VERSION 5.8 ;
BUSBITCHARS "[]" ;
DIVIDERCHAR "/" ;
UNITS
    DATABASE MICRONS 1000 ;
END UNITS

VIA PLL_ANALOG_MACRO_via1_2_2200_440_1_5_410_410
  VIARULE via1Array ;
  CUTSIZE 0.19 0.19 ;
  LAYERS Metal1 Via1 Metal2 ;
  CUTSPACING 0.22 0.22 ;
  ENCLOSURE 0.05 0.125 0.005 0.05 ;
  ROWCOL 1 5 ;
END PLL_ANALOG_MACRO_via1_2_2200_440_1_5_410_410

VIA PLL_ANALOG_MACRO_via2_3_2200_440_1_5_410_410
  VIARULE via2Array ;
  CUTSIZE 0.19 0.19 ;
  LAYERS Metal2 Via2 Metal3 ;
  CUTSPACING 0.22 0.22 ;
  ENCLOSURE 0.005 0.05 0.05 0.005 ;
  ROWCOL 1 5 ;
END PLL_ANALOG_MACRO_via2_3_2200_440_1_5_410_410

VIA PLL_ANALOG_MACRO_via3_4_2200_440_1_5_410_410
  VIARULE via3Array ;
  CUTSIZE 0.19 0.19 ;
  LAYERS Metal3 Via3 Metal4 ;
  CUTSPACING 0.22 0.22 ;
  ENCLOSURE 0.05 0.005 0.005 0.05 ;
  ROWCOL 1 5 ;
END PLL_ANALOG_MACRO_via3_4_2200_440_1_5_410_410

VIA PLL_ANALOG_MACRO_via4_5_2200_440_1_5_410_410
  VIARULE via4Array ;
  CUTSIZE 0.19 0.19 ;
  LAYERS Metal4 Via4 Metal5 ;
  CUTSPACING 0.22 0.22 ;
  ENCLOSURE 0.005 0.05 0.05 0.005 ;
  ROWCOL 1 5 ;
END PLL_ANALOG_MACRO_via4_5_2200_440_1_5_410_410

VIA PLL_ANALOG_MACRO_via5_6_2200_440_1_2_840_840
  VIARULE viaTop1Array ;
  CUTSIZE 0.42 0.42 ;
  LAYERS Metal5 TopVia1 TopMetal1 ;
  CUTSPACING 0.42 0.42 ;
  ENCLOSURE 0.1 0.1 0.47 0.42 ;
  ROWCOL 1 2 ;
END PLL_ANALOG_MACRO_via5_6_2200_440_1_2_840_840

VIA PLL_ANALOG_MACRO_via6_7_5000_5000_2_2_1960_1960
  VIARULE viaTop2Array ;
  CUTSIZE 0.9 0.9 ;
  LAYERS TopMetal1 TopVia2 TopMetal2 ;
  CUTSPACING 1.06 1.06 ;
  ENCLOSURE 1.07 0.5 0.5 1.07 ;
  ROWCOL 2 2 ;
END PLL_ANALOG_MACRO_via6_7_5000_5000_2_2_1960_1960

VIA PLL_ANALOG_MACRO_via6_7_5000_2200_1_2_1960_1960
  VIARULE viaTop2Array ;
  CUTSIZE 0.9 0.9 ;
  LAYERS TopMetal1 TopVia2 TopMetal2 ;
  CUTSPACING 1.06 1.06 ;
  ENCLOSURE 1.07 0.5 0.5 0.65 ;
  ROWCOL 1 2 ;
END PLL_ANALOG_MACRO_via6_7_5000_2200_1_2_1960_1960

VIA PLL_ANALOG_MACRO_via6_7_2200_5000_2_1_1960_1960
  VIARULE viaTop2Array ;
  CUTSIZE 0.9 0.9 ;
  LAYERS TopMetal1 TopVia2 TopMetal2 ;
  CUTSPACING 1.06 1.06 ;
  ENCLOSURE 0.65 0.5 0.5 1.07 ;
  ROWCOL 2 1 ;
END PLL_ANALOG_MACRO_via6_7_2200_5000_2_1_1960_1960

VIA PLL_ANALOG_MACRO_via6_7_2200_2200_1_1_1960_1960
  VIARULE viaTop2Array ;
  CUTSIZE 0.9 0.9 ;
  LAYERS TopMetal1 TopVia2 TopMetal2 ;
  CUTSPACING 1.06 1.06 ;
  ENCLOSURE 0.65 0.5 0.5 0.65 ;
END PLL_ANALOG_MACRO_via6_7_2200_2200_1_1_1960_1960

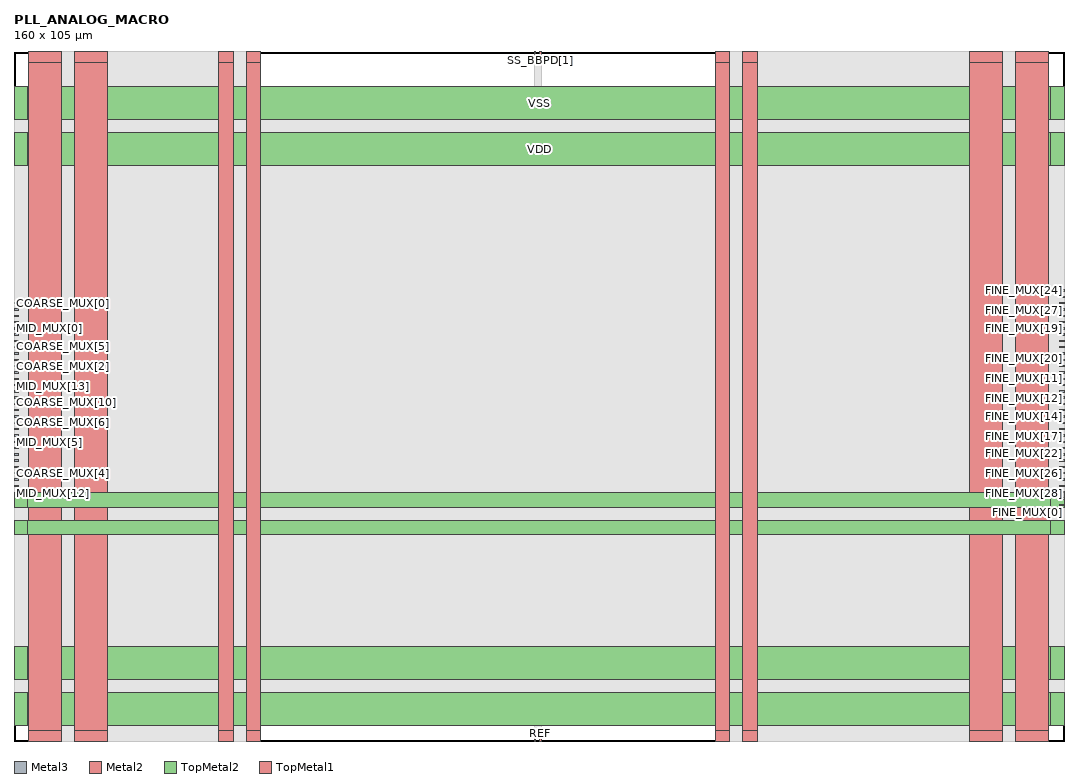
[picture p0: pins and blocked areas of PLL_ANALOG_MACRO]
MACRO PLL_ANALOG_MACRO
  FOREIGN PLL_ANALOG_MACRO 0 0 ;
  CLASS BLOCK ;
  SIZE 160 BY 105 ;
  PIN COARSE_MUX[0]
    DIRECTION INPUT ;
    USE SIGNAL ;
    PORT
      LAYER Metal3 ;
        RECT  0 66.62 0.72 66.82 ;
    END
  END COARSE_MUX[0]
  PIN COARSE_MUX[10]
    DIRECTION INPUT ;
    USE SIGNAL ;
    PORT
      LAYER Metal3 ;
        RECT  0 50.3 0.72 50.5 ;
    END
  END COARSE_MUX[10]
  PIN COARSE_MUX[11]
    DIRECTION INPUT ;
    USE SIGNAL ;
    PORT
      LAYER Metal3 ;
        RECT  0 53.18 0.72 53.38 ;
    END
  END COARSE_MUX[11]
  PIN COARSE_MUX[12]
    DIRECTION INPUT ;
    USE SIGNAL ;
    PORT
      LAYER Metal3 ;
        RECT  0 54.14 0.72 54.34 ;
    END
  END COARSE_MUX[12]
  PIN COARSE_MUX[13]
    DIRECTION INPUT ;
    USE SIGNAL ;
    PORT
      LAYER Metal3 ;
        RECT  0 44.54 0.72 44.74 ;
    END
  END COARSE_MUX[13]
  PIN COARSE_MUX[14]
    DIRECTION INPUT ;
    USE SIGNAL ;
    PORT
      LAYER Metal3 ;
        RECT  0 51.26 0.72 51.46 ;
    END
  END COARSE_MUX[14]
  PIN COARSE_MUX[1]
    DIRECTION INPUT ;
    USE SIGNAL ;
    PORT
      LAYER Metal3 ;
        RECT  0 43.58 0.72 43.78 ;
    END
  END COARSE_MUX[1]
  PIN COARSE_MUX[2]
    DIRECTION INPUT ;
    USE SIGNAL ;
    PORT
      LAYER Metal3 ;
        RECT  0 57.02 0.72 57.22 ;
    END
  END COARSE_MUX[2]
  PIN COARSE_MUX[3]
    DIRECTION INPUT ;
    USE SIGNAL ;
    PORT
      LAYER Metal3 ;
        RECT  0 57.98 0.72 58.18 ;
    END
  END COARSE_MUX[3]
  PIN COARSE_MUX[4]
    DIRECTION INPUT ;
    USE SIGNAL ;
    PORT
      LAYER Metal3 ;
        RECT  0 40.7 0.72 40.9 ;
    END
  END COARSE_MUX[4]
  PIN COARSE_MUX[5]
    DIRECTION INPUT ;
    USE SIGNAL ;
    PORT
      LAYER Metal3 ;
        RECT  0 58.94 0.72 59.14 ;
    END
  END COARSE_MUX[5]
  PIN COARSE_MUX[6]
    DIRECTION INPUT ;
    USE SIGNAL ;
    PORT
      LAYER Metal3 ;
        RECT  0 48.38 0.72 48.58 ;
    END
  END COARSE_MUX[6]
  PIN COARSE_MUX[7]
    DIRECTION INPUT ;
    USE SIGNAL ;
    PORT
      LAYER Metal3 ;
        RECT  0 60.86 0.72 61.06 ;
    END
  END COARSE_MUX[7]
  PIN COARSE_MUX[8]
    DIRECTION INPUT ;
    USE SIGNAL ;
    PORT
      LAYER Metal3 ;
        RECT  0 49.34 0.72 49.54 ;
    END
  END COARSE_MUX[8]
  PIN COARSE_MUX[9]
    DIRECTION INPUT ;
    USE SIGNAL ;
    PORT
      LAYER Metal3 ;
        RECT  0 61.82 0.72 62.02 ;
    END
  END COARSE_MUX[9]
  PIN DCO_EN
    DIRECTION INPUT ;
    USE SIGNAL ;
    PORT
      LAYER Metal2 ;
        RECT  79.28 0 79.48 0.72 ;
    END
  END DCO_EN
  PIN FINE_MUX[0]
    DIRECTION INPUT ;
    USE SIGNAL ;
    PORT
      LAYER Metal3 ;
        RECT  159.28 35.9 160 36.1 ;
    END
  END FINE_MUX[0]
  PIN FINE_MUX[10]
    DIRECTION INPUT ;
    USE SIGNAL ;
    PORT
      LAYER Metal3 ;
        RECT  159.28 67.58 160 67.78 ;
    END
  END FINE_MUX[10]
  PIN FINE_MUX[11]
    DIRECTION INPUT ;
    USE SIGNAL ;
    PORT
      LAYER Metal3 ;
        RECT  159.28 55.1 160 55.3 ;
    END
  END FINE_MUX[11]
  PIN FINE_MUX[12]
    DIRECTION INPUT ;
    USE SIGNAL ;
    PORT
      LAYER Metal3 ;
        RECT  159.28 53.18 160 53.38 ;
    END
  END FINE_MUX[12]
  PIN FINE_MUX[13]
    DIRECTION INPUT ;
    USE SIGNAL ;
    PORT
      LAYER Metal3 ;
        RECT  159.28 65.66 160 65.86 ;
    END
  END FINE_MUX[13]
  PIN FINE_MUX[14]
    DIRECTION INPUT ;
    USE SIGNAL ;
    PORT
      LAYER Metal3 ;
        RECT  159.28 49.34 160 49.54 ;
    END
  END FINE_MUX[14]
  PIN FINE_MUX[15]
    DIRECTION INPUT ;
    USE SIGNAL ;
    PORT
      LAYER Metal3 ;
        RECT  159.28 61.82 160 62.02 ;
    END
  END FINE_MUX[15]
  PIN FINE_MUX[16]
    DIRECTION INPUT ;
    USE SIGNAL ;
    PORT
      LAYER Metal3 ;
        RECT  159.28 54.14 160 54.34 ;
    END
  END FINE_MUX[16]
  PIN FINE_MUX[17]
    DIRECTION INPUT ;
    USE SIGNAL ;
    PORT
      LAYER Metal3 ;
        RECT  159.28 47.42 160 47.62 ;
    END
  END FINE_MUX[17]
  PIN FINE_MUX[18]
    DIRECTION INPUT ;
    USE SIGNAL ;
    PORT
      LAYER Metal3 ;
        RECT  159.28 46.46 160 46.66 ;
    END
  END FINE_MUX[18]
  PIN FINE_MUX[19]
    DIRECTION INPUT ;
    USE SIGNAL ;
    PORT
      LAYER Metal3 ;
        RECT  159.28 62.78 160 62.98 ;
    END
  END FINE_MUX[19]
  PIN FINE_MUX[1]
    DIRECTION INPUT ;
    USE SIGNAL ;
    PORT
      LAYER Metal3 ;
        RECT  159.28 63.74 160 63.94 ;
    END
  END FINE_MUX[1]
  PIN FINE_MUX[20]
    DIRECTION INPUT ;
    USE SIGNAL ;
    PORT
      LAYER Metal3 ;
        RECT  159.28 57.02 160 57.22 ;
    END
  END FINE_MUX[20]
  PIN FINE_MUX[21]
    DIRECTION INPUT ;
    USE SIGNAL ;
    PORT
      LAYER Metal3 ;
        RECT  159.28 45.5 160 45.7 ;
    END
  END FINE_MUX[21]
  PIN FINE_MUX[22]
    DIRECTION INPUT ;
    USE SIGNAL ;
    PORT
      LAYER Metal3 ;
        RECT  159.28 42.62 160 42.82 ;
    END
  END FINE_MUX[22]
  PIN FINE_MUX[23]
    DIRECTION INPUT ;
    USE SIGNAL ;
    PORT
      LAYER Metal3 ;
        RECT  159.28 56.06 160 56.26 ;
    END
  END FINE_MUX[23]
  PIN FINE_MUX[24]
    DIRECTION INPUT ;
    USE SIGNAL ;
    PORT
      LAYER Metal3 ;
        RECT  159.28 68.54 160 68.74 ;
    END
  END FINE_MUX[24]
  PIN FINE_MUX[25]
    DIRECTION INPUT ;
    USE SIGNAL ;
    PORT
      LAYER Metal3 ;
        RECT  159.28 50.3 160 50.5 ;
    END
  END FINE_MUX[25]
  PIN FINE_MUX[26]
    DIRECTION INPUT ;
    USE SIGNAL ;
    PORT
      LAYER Metal3 ;
        RECT  159.28 40.7 160 40.9 ;
    END
  END FINE_MUX[26]
  PIN FINE_MUX[27]
    DIRECTION INPUT ;
    USE SIGNAL ;
    PORT
      LAYER Metal3 ;
        RECT  159.28 66.62 160 66.82 ;
    END
  END FINE_MUX[27]
  PIN FINE_MUX[28]
    DIRECTION INPUT ;
    USE SIGNAL ;
    PORT
      LAYER Metal3 ;
        RECT  159.28 38.78 160 38.98 ;
    END
  END FINE_MUX[28]
  PIN FINE_MUX[29]
    DIRECTION INPUT ;
    USE SIGNAL ;
    PORT
      LAYER Metal3 ;
        RECT  159.28 48.38 160 48.58 ;
    END
  END FINE_MUX[29]
  PIN FINE_MUX[2]
    DIRECTION INPUT ;
    USE SIGNAL ;
    PORT
      LAYER Metal3 ;
        RECT  159.28 44.54 160 44.74 ;
    END
  END FINE_MUX[2]
  PIN FINE_MUX[30]
    DIRECTION INPUT ;
    USE SIGNAL ;
    PORT
      LAYER Metal3 ;
        RECT  159.28 57.98 160 58.18 ;
    END
  END FINE_MUX[30]
  PIN FINE_MUX[3]
    DIRECTION INPUT ;
    USE SIGNAL ;
    PORT
      LAYER Metal3 ;
        RECT  159.28 52.22 160 52.42 ;
    END
  END FINE_MUX[3]
  PIN FINE_MUX[4]
    DIRECTION INPUT ;
    USE SIGNAL ;
    PORT
      LAYER Metal3 ;
        RECT  159.28 58.94 160 59.14 ;
    END
  END FINE_MUX[4]
  PIN FINE_MUX[5]
    DIRECTION INPUT ;
    USE SIGNAL ;
    PORT
      LAYER Metal3 ;
        RECT  159.28 37.82 160 38.02 ;
    END
  END FINE_MUX[5]
  PIN FINE_MUX[6]
    DIRECTION INPUT ;
    USE SIGNAL ;
    PORT
      LAYER Metal3 ;
        RECT  159.28 60.86 160 61.06 ;
    END
  END FINE_MUX[6]
  PIN FINE_MUX[7]
    DIRECTION INPUT ;
    USE SIGNAL ;
    PORT
      LAYER Metal3 ;
        RECT  159.28 64.7 160 64.9 ;
    END
  END FINE_MUX[7]
  PIN FINE_MUX[8]
    DIRECTION INPUT ;
    USE SIGNAL ;
    PORT
      LAYER Metal3 ;
        RECT  159.28 41.66 160 41.86 ;
    END
  END FINE_MUX[8]
  PIN FINE_MUX[9]
    DIRECTION INPUT ;
    USE SIGNAL ;
    PORT
      LAYER Metal3 ;
        RECT  159.28 51.26 160 51.46 ;
    END
  END FINE_MUX[9]
  PIN INJ_EDGE
    DIRECTION OUTPUT ;
    USE SIGNAL ;
    PORT
      LAYER Metal3 ;
        RECT  159.28 59.9 160 60.1 ;
    END
  END INJ_EDGE
  PIN INJ_EN
    DIRECTION INPUT ;
    USE SIGNAL ;
    PORT
      LAYER Metal3 ;
        RECT  159.28 36.86 160 37.06 ;
    END
  END INJ_EN
  PIN MID_MUX[0]
    DIRECTION INPUT ;
    USE SIGNAL ;
    PORT
      LAYER Metal3 ;
        RECT  0 62.78 0.72 62.98 ;
    END
  END MID_MUX[0]
  PIN MID_MUX[10]
    DIRECTION INPUT ;
    USE SIGNAL ;
    PORT
      LAYER Metal3 ;
        RECT  0 56.06 0.72 56.26 ;
    END
  END MID_MUX[10]
  PIN MID_MUX[11]
    DIRECTION INPUT ;
    USE SIGNAL ;
    PORT
      LAYER Metal3 ;
        RECT  0 42.62 0.72 42.82 ;
    END
  END MID_MUX[11]
  PIN MID_MUX[12]
    DIRECTION INPUT ;
    USE SIGNAL ;
    PORT
      LAYER Metal3 ;
        RECT  0 38.78 0.72 38.98 ;
    END
  END MID_MUX[12]
  PIN MID_MUX[13]
    DIRECTION INPUT ;
    USE SIGNAL ;
    PORT
      LAYER Metal3 ;
        RECT  0 55.1 0.72 55.3 ;
    END
  END MID_MUX[13]
  PIN MID_MUX[14]
    DIRECTION INPUT ;
    USE SIGNAL ;
    PORT
      LAYER Metal3 ;
        RECT  0 63.74 0.72 63.94 ;
    END
  END MID_MUX[14]
  PIN MID_MUX[1]
    DIRECTION INPUT ;
    USE SIGNAL ;
    PORT
      LAYER Metal3 ;
        RECT  0 47.42 0.72 47.62 ;
    END
  END MID_MUX[1]
  PIN MID_MUX[2]
    DIRECTION INPUT ;
    USE SIGNAL ;
    PORT
      LAYER Metal3 ;
        RECT  0 45.5 0.72 45.7 ;
    END
  END MID_MUX[2]
  PIN MID_MUX[3]
    DIRECTION INPUT ;
    USE SIGNAL ;
    PORT
      LAYER Metal3 ;
        RECT  0 64.7 0.72 64.9 ;
    END
  END MID_MUX[3]
  PIN MID_MUX[4]
    DIRECTION INPUT ;
    USE SIGNAL ;
    PORT
      LAYER Metal3 ;
        RECT  0 65.66 0.72 65.86 ;
    END
  END MID_MUX[4]
  PIN MID_MUX[5]
    DIRECTION INPUT ;
    USE SIGNAL ;
    PORT
      LAYER Metal3 ;
        RECT  0 46.46 0.72 46.66 ;
    END
  END MID_MUX[5]
  PIN MID_MUX[6]
    DIRECTION INPUT ;
    USE SIGNAL ;
    PORT
      LAYER Metal3 ;
        RECT  0 41.66 0.72 41.86 ;
    END
  END MID_MUX[6]
  PIN MID_MUX[7]
    DIRECTION INPUT ;
    USE SIGNAL ;
    PORT
      LAYER Metal3 ;
        RECT  0 52.22 0.72 52.42 ;
    END
  END MID_MUX[7]
  PIN MID_MUX[8]
    DIRECTION INPUT ;
    USE SIGNAL ;
    PORT
      LAYER Metal3 ;
        RECT  0 59.9 0.72 60.1 ;
    END
  END MID_MUX[8]
  PIN MID_MUX[9]
    DIRECTION INPUT ;
    USE SIGNAL ;
    PORT
      LAYER Metal3 ;
        RECT  0 39.74 0.72 39.94 ;
    END
  END MID_MUX[9]
  PIN MID_OUT
    DIRECTION OUTPUT ;
    USE SIGNAL ;
    PORT
      LAYER Metal3 ;
        RECT  159.28 43.58 160 43.78 ;
    END
  END MID_OUT
  PIN OUT
    DIRECTION OUTPUT ;
    USE SIGNAL ;
    PORT
      LAYER Metal3 ;
        RECT  159.28 39.74 160 39.94 ;
    END
  END OUT
  PIN REF
    DIRECTION INPUT ;
    USE SIGNAL ;
    PORT
      LAYER Metal2 ;
        RECT  80.12 0 80.32 0.72 ;
    END
  END REF
  PIN SS_BBPD[0]
    DIRECTION OUTPUT ;
    USE SIGNAL ;
    PORT
      LAYER Metal2 ;
        RECT  79.28 104.28 79.48 105 ;
    END
  END SS_BBPD[0]
  PIN SS_BBPD[1]
    DIRECTION OUTPUT ;
    USE SIGNAL ;
    PORT
      LAYER Metal2 ;
        RECT  80.12 104.28 80.32 105 ;
    END
  END SS_BBPD[1]
  PIN VSS
    DIRECTION INOUT ;
    USE GROUND ;
    PORT
      LAYER TopMetal2 ;
        RECT  158 35.6 160 37.8 ;
        RECT  0 35.6 2 37.8 ;
        RECT  0 35.6 160 37.8 ;
      LAYER TopMetal1 ;
        RECT  111.02 103.36 113.22 105 ;
        RECT  111.02 0 113.22 1.64 ;
        RECT  111.02 0 113.22 105 ;
        RECT  35.42 103.36 37.62 105 ;
        RECT  35.42 0 37.62 1.64 ;
        RECT  35.42 0 37.62 105 ;
      LAYER TopMetal2 ;
        RECT  158 94.66 160 99.66 ;
        RECT  0 94.66 2 99.66 ;
        RECT  0 94.66 160 99.66 ;
        RECT  158 2.4 160 7.4 ;
        RECT  0 2.4 2 7.4 ;
        RECT  0 2.4 160 7.4 ;
      LAYER TopMetal1 ;
        RECT  152.62 103.36 157.62 105 ;
        RECT  152.62 0 157.62 1.64 ;
        RECT  152.62 0 157.62 105 ;
        RECT  2.22 103.36 7.22 105 ;
        RECT  2.22 0 7.22 1.64 ;
        RECT  2.22 0 7.22 105 ;
    END
  END VSS
  PIN VDD
    DIRECTION INOUT ;
    USE POWER ;
    PORT
      LAYER TopMetal2 ;
        RECT  158 31.4 160 33.6 ;
        RECT  0 31.4 2 33.6 ;
        RECT  0 31.4 160 33.6 ;
      LAYER TopMetal1 ;
        RECT  106.82 103.36 109.02 105 ;
        RECT  106.82 0 109.02 1.64 ;
        RECT  106.82 0 109.02 105 ;
        RECT  31.22 103.36 33.42 105 ;
        RECT  31.22 0 33.42 1.64 ;
        RECT  31.22 0 33.42 105 ;
      LAYER TopMetal2 ;
        RECT  158 87.66 160 92.66 ;
        RECT  0 87.66 2 92.66 ;
        RECT  0 87.66 160 92.66 ;
        RECT  158 9.4 160 14.4 ;
        RECT  0 9.4 2 14.4 ;
        RECT  0 9.4 160 14.4 ;
      LAYER TopMetal1 ;
        RECT  145.62 103.36 150.62 105 ;
        RECT  145.62 0 150.62 1.64 ;
        RECT  145.62 0 150.62 105 ;
        RECT  9.22 103.36 14.22 105 ;
        RECT  9.22 0 14.22 1.64 ;
        RECT  9.22 0 14.22 105 ;
    END
  END VDD
  OBS
    LAYER Metal1 ;
     RECT  18.72 18.68 141.12 83.38 ;
    LAYER Metal2 ;
     RECT  79.28 0.48 80.32 5.38 ;
     RECT  103.64 5.18 103.84 6.14 ;
     RECT  79.28 5.38 79.48 6.34 ;
     RECT  101.96 6.14 103.84 18.755 ;
     RECT  35.6 18.755 37.44 22.535 ;
     RECT  31.4 22.535 37.44 28.22 ;
     RECT  23.42 28.22 37.44 30.63 ;
     RECT  22.58 30.63 37.44 31.1 ;
     RECT  22.58 31.1 37.48 31.59 ;
     RECT  22.58 31.59 38.53 32.06 ;
     RECT  57.02 31.58 58.69 32.06 ;
     RECT  135.14 32.3 135.34 33.02 ;
     RECT  135.14 33.02 138.28 34.94 ;
     RECT  57.02 32.06 60.16 35.42 ;
     RECT  76.34 35.055 76.54 35.42 ;
     RECT  101.96 18.755 113.04 35.42 ;
     RECT  56.695 35.42 61.525 35.425 ;
     RECT  76.34 35.42 113.04 35.43 ;
     RECT  133.46 34.94 138.28 35.625 ;
     RECT  20.9 32.06 38.53 35.66 ;
     RECT  56.055 35.425 63.52 35.9 ;
     RECT  74.66 35.43 113.04 35.9 ;
     RECT  55.34 35.9 63.52 36.86 ;
     RECT  20.9 35.66 45.46 37.7 ;
     RECT  55.34 36.86 63.94 37.7 ;
     RECT  20.9 37.7 63.94 37.82 ;
     RECT  74.66 35.9 117.28 37.82 ;
     RECT  20.9 37.82 117.7 38.78 ;
     RECT  132.9 35.625 138.28 38.78 ;
     RECT  20.9 38.78 138.28 39.26 ;
     RECT  20.48 39.26 138.28 39.74 ;
     RECT  151.52 39.74 151.72 41.18 ;
     RECT  20.06 39.74 138.28 42.15 ;
     RECT  20.06 42.15 138.91 42.72 ;
     RECT  151.1 41.18 151.72 45.7 ;
     RECT  151.52 45.7 151.72 46.18 ;
     RECT  20.06 42.72 138.7 47.62 ;
     RECT  20.48 47.62 138.7 50.98 ;
     RECT  20.48 50.98 137.86 61.82 ;
     RECT  20.48 61.82 138.28 62.5 ;
     RECT  152.36 61.34 152.56 62.98 ;
     RECT  6.2 49.82 6.4 66.82 ;
     RECT  20.9 62.5 138.28 66.82 ;
     RECT  20.9 66.82 113.04 67.3 ;
     RECT  20.9 67.3 66.88 69.22 ;
     RECT  124.64 66.82 138.28 69.51 ;
     RECT  124.64 69.51 138.91 70.08 ;
     RECT  20.9 69.22 66.46 70.18 ;
     RECT  79.28 67.3 113.04 70.18 ;
     RECT  125.06 70.08 138.28 70.18 ;
     RECT  21.57 70.18 66.38 70.215 ;
     RECT  127.16 70.18 136.94 70.215 ;
     RECT  21.57 70.215 57.29 70.31 ;
     RECT  127.16 70.215 134.92 70.65 ;
     RECT  21.57 70.31 57.245 70.66 ;
     RECT  132.535 70.65 134.92 70.66 ;
     RECT  22.16 70.66 57.22 70.755 ;
     RECT  57.02 70.755 57.22 71.14 ;
     RECT  79.28 70.18 95.02 73.54 ;
     RECT  22.16 70.755 43.78 74.02 ;
     RECT  79.28 73.54 81.16 74.5 ;
     RECT  25.94 74.02 43.78 74.97 ;
     RECT  31.4 74.97 37.44 79.525 ;
     RECT  107 70.18 113.04 79.525 ;
     RECT  31.4 79.525 33.24 83.305 ;
     RECT  107 79.525 108.84 83.305 ;
     RECT  79.28 74.5 79.48 94.46 ;
     RECT  94.82 73.54 95.02 94.66 ;
     RECT  79.28 94.46 80.32 104.64 ;
    LAYER Metal3 ;
     RECT  0.42 38.78 6.4 66.82 ;
     RECT  6.4 38.78 20.9 65.86 ;
     RECT  20.9 32.54 21.57 70.18 ;
     RECT  21.57 32.54 22.16 70.66 ;
     RECT  22.16 32.54 22.58 74.02 ;
     RECT  22.58 31.1 25.94 74.02 ;
     RECT  25.94 31.1 31.355 74.5 ;
     RECT  31.355 22.58 33.285 83.26 ;
     RECT  33.285 22.58 35.555 79.48 ;
     RECT  35.555 18.8 37.485 79.48 ;
     RECT  37.485 32.06 38.53 74.5 ;
     RECT  38.53 38.3 43.78 74.5 ;
     RECT  43.78 38.3 55.34 70.66 ;
     RECT  55.34 35.9 56.6 70.66 ;
     RECT  56.6 35.9 57.22 71.14 ;
     RECT  57.22 35.9 58.11 70.18 ;
     RECT  58.11 35.9 59.01 66.34 ;
     RECT  59.01 35.42 61.525 66.34 ;
     RECT  61.525 35.9 63.52 66.34 ;
     RECT  63.52 37.82 74.66 66.34 ;
     RECT  74.66 35.9 76.34 66.34 ;
     RECT  76.34 35.42 79.28 66.34 ;
     RECT  79.28 6.14 80.12 6.34 ;
     RECT  79.28 35.42 80.96 69.22 ;
     RECT  80.96 35.42 84.1 73.54 ;
     RECT  84.1 35.42 89.56 69.22 ;
     RECT  89.56 35.42 92.92 37.06 ;
     RECT  89.56 46.94 93.98 69.22 ;
     RECT  80.12 94.46 95.02 94.66 ;
     RECT  93.98 46.94 101.12 70.18 ;
     RECT  80.12 5.18 102.16 6.34 ;
     RECT  102.16 5.18 103.84 5.38 ;
     RECT  101.12 40.7 104.48 70.18 ;
     RECT  104.48 39.26 105.595 70.18 ;
     RECT  105.595 35.9 106.955 70.18 ;
     RECT  106.955 22.58 108.885 83.26 ;
     RECT  108.885 22.58 111.155 79.48 ;
     RECT  111.155 18.8 113.085 79.48 ;
     RECT  113.085 35.9 117.28 66.82 ;
     RECT  117.28 37.82 124.64 66.82 ;
     RECT  124.64 37.82 136.695 70.18 ;
     RECT  136.695 35.9 138.91 70.18 ;
     RECT  138.91 35.9 159.6 68.74 ;
    LAYER Metal4 ;
     RECT  35.6 18.755 37.44 22.535 ;
     RECT  111.2 18.755 113.04 22.535 ;
     RECT  31.4 22.535 37.44 41.66 ;
     RECT  31.4 41.66 39.58 47.14 ;
     RECT  71.3 45.5 71.5 47.62 ;
     RECT  6.2 57.02 6.4 57.7 ;
     RECT  53.24 50.78 53.44 57.7 ;
     RECT  21.32 59.42 21.52 62.98 ;
     RECT  31.4 47.14 37.44 79.525 ;
     RECT  107 22.535 113.04 79.525 ;
     RECT  31.4 79.525 33.24 83.305 ;
     RECT  107 79.525 108.84 83.305 ;
    LAYER Metal5 ;
     RECT  6.2 57.5 31.355 57.7 ;
     RECT  31.355 22.37 33.285 83.47 ;
     RECT  33.285 22.37 35.555 79.69 ;
     RECT  35.555 18.59 37.485 79.69 ;
     RECT  37.485 57.5 53.44 57.7 ;
     RECT  106.955 22.37 108.885 83.47 ;
     RECT  108.885 22.37 111.155 79.69 ;
     RECT  111.155 18.59 113.085 79.69 ;
    LAYER TopMetal1 ;
     RECT  2.22 0 37.62 105 ;
     RECT  106.82 0 157.62 105 ;
    LAYER TopMetal2 ;
     RECT  0 2.4 160 99.66 ;
  END
END PLL_ANALOG_MACRO
END LIBRARY
